VERSION 5.8 ;
BUSBITCHARS "[]" ;
DIVIDERCHAR "/" ;
UNITS
    DATABASE MICRONS 1000 ;
END UNITS

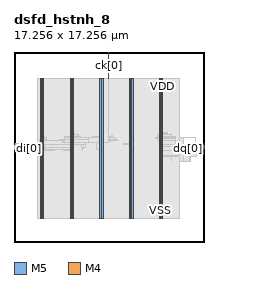
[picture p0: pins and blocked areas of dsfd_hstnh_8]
MACRO dsfd_hstnh_8
  FOREIGN dsfd_hstnh_8 0 0 ;
  CLASS BLOCK ;
  SIZE 17.256 BY 17.256 ;
  PIN ck[0]
    DIRECTION INPUT ;
    USE SIGNAL ;
    PORT
      LAYER M5 ;
        RECT  8.592 17.172 8.616 17.256 ;
    END
    PORT
      LAYER M5 ;
        RECT  8.592 14.873 8.616 17.232 ;
    END
  END ck[0]
  PIN di[0]
    DIRECTION INPUT ;
    USE SIGNAL ;
    PORT
      LAYER M4 ;
        RECT  0 8.448 0.084 8.472 ;
    END
  END di[0]
  PIN di[1]
    DIRECTION INPUT ;
    USE SIGNAL ;
    PORT
      LAYER M4 ;
        RECT  0 8.496 0.084 8.52 ;
    END
  END di[1]
  PIN di[2]
    DIRECTION INPUT ;
    USE SIGNAL ;
    PORT
      LAYER M4 ;
        RECT  0 8.544 0.084 8.568 ;
    END
  END di[2]
  PIN di[3]
    DIRECTION INPUT ;
    USE SIGNAL ;
    PORT
      LAYER M4 ;
        RECT  0 8.592 0.084 8.616 ;
    END
  END di[3]
  PIN di[4]
    DIRECTION INPUT ;
    USE SIGNAL ;
    PORT
      LAYER M4 ;
        RECT  0 8.64 0.084 8.664 ;
    END
  END di[4]
  PIN di[5]
    DIRECTION INPUT ;
    USE SIGNAL ;
    PORT
      LAYER M4 ;
        RECT  0 8.688 0.084 8.712 ;
    END
  END di[5]
  PIN di[6]
    DIRECTION INPUT ;
    USE SIGNAL ;
    PORT
      LAYER M4 ;
        RECT  0 8.736 0.084 8.76 ;
    END
  END di[6]
  PIN di[7]
    DIRECTION INPUT ;
    USE SIGNAL ;
    PORT
      LAYER M4 ;
        RECT  0 8.784 0.084 8.808 ;
    END
  END di[7]
  PIN dq[0]
    DIRECTION OUTPUT ;
    USE SIGNAL ;
    PORT
      LAYER M4 ;
        RECT  17.172 8.448 17.256 8.472 ;
    END
  END dq[0]
  PIN dq[1]
    DIRECTION OUTPUT ;
    USE SIGNAL ;
    PORT
      LAYER M4 ;
        RECT  17.172 8.496 17.256 8.52 ;
    END
  END dq[1]
  PIN dq[2]
    DIRECTION OUTPUT ;
    USE SIGNAL ;
    PORT
      LAYER M4 ;
        RECT  17.172 8.544 17.256 8.568 ;
    END
  END dq[2]
  PIN dq[3]
    DIRECTION OUTPUT ;
    USE SIGNAL ;
    PORT
      LAYER M4 ;
        RECT  17.172 8.592 17.256 8.616 ;
    END
  END dq[3]
  PIN dq[4]
    DIRECTION OUTPUT ;
    USE SIGNAL ;
    PORT
      LAYER M4 ;
        RECT  17.172 8.64 17.256 8.664 ;
    END
  END dq[4]
  PIN dq[5]
    DIRECTION OUTPUT ;
    USE SIGNAL ;
    PORT
      LAYER M4 ;
        RECT  17.172 8.688 17.256 8.712 ;
    END
  END dq[5]
  PIN dq[6]
    DIRECTION OUTPUT ;
    USE SIGNAL ;
    PORT
      LAYER M4 ;
        RECT  17.172 8.736 17.256 8.76 ;
    END
  END dq[6]
  PIN dq[7]
    DIRECTION OUTPUT ;
    USE SIGNAL ;
    PORT
      LAYER M4 ;
        RECT  17.172 8.784 17.256 8.808 ;
    END
  END dq[7]
  PIN VDD
    DIRECTION INOUT ;
    USE POWER ;
    PORT
      LAYER M5 ;
        RECT  13.392 2.151 13.512 14.873 ;
        RECT  10.692 2.151 10.812 14.873 ;
        RECT  7.992 2.151 8.112 14.873 ;
        RECT  5.292 2.151 5.412 14.873 ;
        RECT  2.592 2.151 2.712 14.873 ;
    END
  END VDD
  PIN VSS
    DIRECTION INOUT ;
    USE GROUND ;
    PORT
      LAYER M5 ;
        RECT  13.2 2.137 13.32 14.859 ;
        RECT  10.5 2.137 10.62 14.859 ;
        RECT  7.8 2.137 7.92 14.859 ;
        RECT  5.1 2.137 5.22 14.859 ;
        RECT  2.4 2.137 2.52 14.859 ;
    END
  END VSS
  # OT_OBS_CLOSED layer=M5 d_um=1.536 added=0
  OBS
    LAYER RVTN ;
     RECT  2.16 2.16 15.066 2.295 ;
     RECT  2.16 2.565 15.066 2.835 ;
     RECT  2.16 3.105 15.066 3.375 ;
     RECT  2.16 3.645 15.066 3.915 ;
     RECT  2.16 4.185 15.066 4.455 ;
     RECT  2.16 4.725 15.066 4.995 ;
     RECT  2.16 5.265 15.066 5.535 ;
     RECT  2.16 5.805 15.066 6.075 ;
     RECT  2.16 6.345 15.066 6.615 ;
     RECT  2.16 6.885 15.066 7.155 ;
     RECT  2.16 7.425 15.066 7.695 ;
     RECT  2.16 7.965 15.066 8.235 ;
     RECT  2.16 8.505 15.066 8.775 ;
     RECT  2.16 9.045 15.066 9.315 ;
     RECT  2.16 9.585 15.066 9.855 ;
     RECT  2.16 10.125 15.066 10.395 ;
     RECT  2.16 10.665 15.066 10.935 ;
     RECT  2.16 11.205 15.066 11.475 ;
     RECT  2.16 11.745 15.066 12.015 ;
     RECT  2.16 12.285 15.066 12.555 ;
     RECT  2.16 12.825 15.066 13.095 ;
     RECT  2.16 13.365 15.066 13.635 ;
     RECT  2.16 13.905 15.066 14.175 ;
     RECT  2.16 14.445 15.066 14.715 ;
    LAYER RVTP ;
     RECT  2.16 2.295 15.066 2.565 ;
     RECT  2.16 2.835 15.066 3.105 ;
     RECT  2.16 3.375 15.066 3.645 ;
     RECT  2.16 3.915 15.066 4.185 ;
     RECT  2.16 4.455 15.066 4.725 ;
     RECT  2.16 4.995 15.066 5.265 ;
     RECT  2.16 5.535 15.066 5.805 ;
     RECT  2.16 6.075 15.066 6.345 ;
     RECT  2.16 6.615 15.066 6.885 ;
     RECT  2.16 7.155 15.066 7.425 ;
     RECT  2.16 7.695 15.066 7.965 ;
     RECT  2.16 8.235 15.066 8.505 ;
     RECT  2.16 8.775 15.066 9.045 ;
     RECT  2.16 9.315 15.066 9.585 ;
     RECT  2.16 9.855 15.066 10.125 ;
     RECT  2.16 10.395 15.066 10.665 ;
     RECT  2.16 10.935 15.066 11.205 ;
     RECT  2.16 11.475 15.066 11.745 ;
     RECT  2.16 12.015 15.066 12.285 ;
     RECT  2.16 12.555 15.066 12.825 ;
     RECT  2.16 13.095 15.066 13.365 ;
     RECT  2.16 13.635 15.066 13.905 ;
     RECT  2.16 14.175 15.066 14.445 ;
     RECT  2.16 14.715 15.066 14.85 ;
    LAYER M1 ;
     RECT  2.16 2.151 15.066 14.859 ;
    LAYER M2 ;
     RECT  2.16 2.151 15.066 14.859 ;
     RECT  15.066 7.326 15.431 9.504 ;
     RECT  15.431 7.326 16.007 8.154 ;
     RECT  15.431 9.486 16.511 9.504 ;
     RECT  16.007 7.776 16.547 8.154 ;
     RECT  16.547 8.136 16.583 8.154 ;
    LAYER M3 ;
     RECT  2.415 2.143 2.505 2.413 ;
     RECT  5.115 2.143 5.205 2.413 ;
     RECT  7.815 2.143 7.905 2.413 ;
     RECT  10.515 2.143 10.605 2.413 ;
     RECT  13.215 2.143 13.305 2.413 ;
     RECT  14.328 7.393 14.346 7.735 ;
     RECT  13.215 2.413 13.497 7.771 ;
     RECT  14.328 7.735 14.742 7.771 ;
     RECT  15.984 7.321 16.002 7.771 ;
     RECT  13.215 7.771 14.85 7.861 ;
     RECT  15.984 7.771 16.542 8.131 ;
     RECT  2.415 2.413 2.697 8.275 ;
     RECT  5.115 2.413 5.397 8.275 ;
     RECT  2.415 8.275 2.826 8.311 ;
     RECT  5.004 8.275 5.397 8.311 ;
     RECT  13.215 7.861 14.922 8.311 ;
     RECT  15.984 8.131 16.578 8.311 ;
     RECT  2.415 8.311 3.654 8.401 ;
     RECT  4.5 8.311 5.397 8.401 ;
     RECT  7.815 2.413 8.097 8.401 ;
     RECT  2.415 8.401 5.397 8.437 ;
     RECT  6.192 8.311 6.21 8.509 ;
     RECT  6.192 8.509 6.354 8.545 ;
     RECT  6.192 8.545 6.462 8.581 ;
     RECT  2.34 8.437 5.397 8.587 ;
     RECT  13.215 8.311 16.578 8.669 ;
     RECT  0.324 8.635 0.342 8.683 ;
     RECT  16.488 8.669 16.578 8.717 ;
     RECT  0.324 8.683 0.414 8.764 ;
     RECT  0.18 8.764 0.414 8.813 ;
     RECT  13.215 8.669 15.426 8.813 ;
     RECT  2.304 8.587 5.397 8.843 ;
     RECT  2.34 8.843 5.397 8.851 ;
     RECT  6.12 8.581 6.462 8.851 ;
     RECT  10.515 2.413 10.797 8.851 ;
     RECT  0.18 8.813 0.198 8.909 ;
     RECT  9.9 8.851 10.797 8.969 ;
     RECT  15.408 8.813 15.426 8.969 ;
     RECT  7.524 8.401 8.097 9.085 ;
     RECT  7.524 9.085 8.406 9.121 ;
     RECT  7.524 9.121 8.766 9.211 ;
     RECT  2.34 8.851 6.462 9.239 ;
     RECT  4.14 9.239 6.462 9.247 ;
     RECT  7.524 9.211 9.414 9.247 ;
     RECT  13.215 8.813 14.67 9.247 ;
     RECT  2.34 9.239 2.934 9.275 ;
     RECT  4.14 9.247 9.414 9.275 ;
     RECT  4.572 9.275 9.414 9.347 ;
     RECT  13.032 9.247 14.67 9.391 ;
     RECT  4.572 9.347 9.198 9.485 ;
     RECT  2.415 9.275 2.934 9.509 ;
     RECT  7.092 9.485 9.198 9.509 ;
     RECT  12.816 9.391 14.67 9.509 ;
     RECT  16.488 8.717 16.506 9.509 ;
     RECT  2.415 9.509 2.754 9.545 ;
     RECT  4.572 9.485 6.066 9.545 ;
     RECT  7.092 9.509 8.982 9.545 ;
     RECT  13.032 9.509 14.67 9.545 ;
     RECT  5.115 9.545 6.066 9.617 ;
     RECT  8.856 9.545 8.982 9.617 ;
     RECT  8.892 9.617 8.982 9.689 ;
     RECT  5.115 9.617 5.886 9.779 ;
     RECT  13.032 9.545 14.274 9.779 ;
     RECT  5.115 9.779 5.526 9.815 ;
     RECT  13.215 9.779 13.986 9.887 ;
     RECT  13.215 9.887 13.95 9.959 ;
     RECT  2.415 9.545 2.697 14.597 ;
     RECT  5.115 9.815 5.397 14.597 ;
     RECT  7.815 9.545 8.097 14.597 ;
     RECT  10.515 8.969 10.797 14.597 ;
     RECT  13.215 9.959 13.497 14.597 ;
     RECT  2.607 14.597 2.697 14.867 ;
     RECT  5.307 14.597 5.397 14.867 ;
     RECT  8.007 14.597 8.097 14.867 ;
     RECT  10.707 14.597 10.797 14.867 ;
     RECT  13.407 14.597 13.497 14.867 ;
    LAYER M4 ;
     RECT  0.06 8.448 0.133 8.808 ;
     RECT  0.133 8.448 0.169 8.856 ;
     RECT  0.169 8.448 2.408 8.904 ;
     RECT  2.408 2.148 2.512 14.592 ;
     RECT  2.512 2.418 2.6 14.592 ;
     RECT  2.6 2.418 2.704 14.862 ;
     RECT  2.704 8.496 2.765 8.808 ;
     RECT  2.765 8.496 2.837 8.52 ;
     RECT  4.417 9.072 4.561 9.096 ;
     RECT  4.561 9.072 5.108 9.288 ;
     RECT  5.108 2.148 5.212 14.592 ;
     RECT  5.212 2.418 5.3 14.592 ;
     RECT  5.3 2.418 5.404 14.862 ;
     RECT  5.404 9.024 6.757 9.288 ;
     RECT  6.757 9.024 7.808 9.48 ;
     RECT  7.808 2.148 7.912 14.592 ;
     RECT  7.912 2.418 8 14.592 ;
     RECT  8 2.418 8.104 14.862 ;
     RECT  8.104 9.024 8.627 9.528 ;
     RECT  8.627 9.504 8.993 9.528 ;
     RECT  10.508 2.148 10.612 14.592 ;
     RECT  10.612 2.418 10.7 14.592 ;
     RECT  10.7 2.418 10.804 14.862 ;
     RECT  13.208 2.148 13.312 14.592 ;
     RECT  13.312 2.418 13.4 14.592 ;
     RECT  13.4 2.418 13.504 14.862 ;
     RECT  14.893 8.784 15.397 8.808 ;
     RECT  15.397 8.544 15.973 8.808 ;
     RECT  15.973 8.496 16.513 8.808 ;
     RECT  16.513 8.448 17.196 8.808 ;
    LAYER M5 ;
     RECT  2.4 2.137 2.52 2.151 ;
     RECT  5.1 2.137 5.22 2.151 ;
     RECT  7.8 2.137 7.92 2.151 ;
     RECT  10.5 2.137 10.62 2.151 ;
     RECT  13.2 2.137 13.32 2.151 ;
     RECT  0.144 8.725 0.168 8.867 ;
     RECT  7.8 2.151 8.112 9.013 ;
     RECT  2.4 2.151 2.712 14.859 ;
     RECT  5.1 2.151 5.412 14.859 ;
     RECT  7.8 9.013 8.616 14.859 ;
     RECT  10.5 2.151 10.812 14.859 ;
     RECT  13.2 2.151 13.512 14.859 ;
     RECT  2.592 14.859 2.712 14.873 ;
     RECT  5.292 14.859 5.412 14.873 ;
     RECT  7.992 14.859 8.616 14.873 ;
     RECT  10.692 14.859 10.812 14.873 ;
     RECT  13.392 14.859 13.512 14.873 ;
  END
END dsfd_hstnh_8
END LIBRARY
